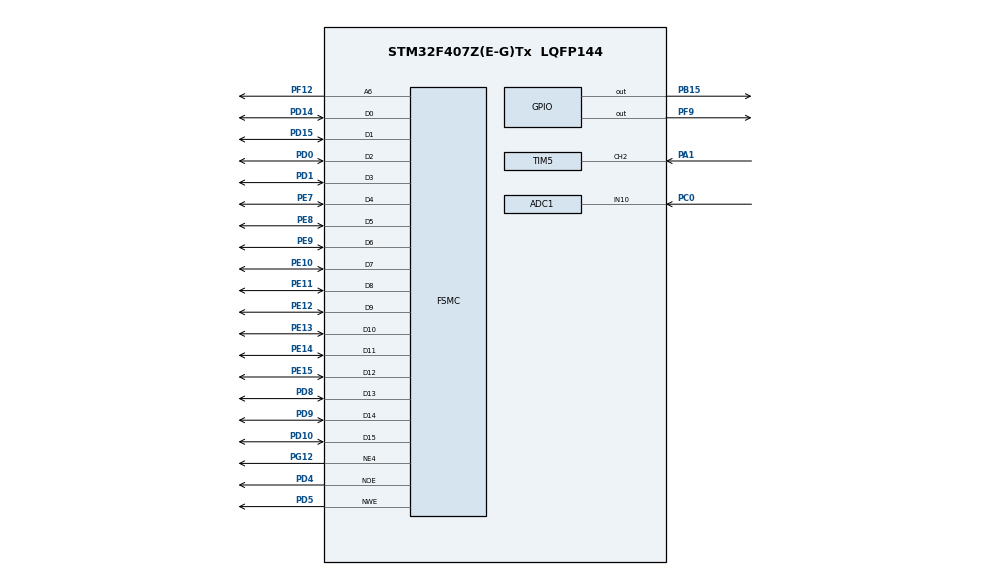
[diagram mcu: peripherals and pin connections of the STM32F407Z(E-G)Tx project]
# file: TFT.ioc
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ADC1.Channel-0\#ChannelRegularConversion=ADC_CHANNEL_10
ADC1.DMAContinuousRequests=ENABLE
ADC1.ExternalTrigConv=ADC_EXTERNALTRIGCONV_T2_TRGO
ADC1.InjNumberOfConversion=0
ADC1.NbrOfConversion=1
ADC1.NbrOfConversionFlag=1
ADC1.Rank-0\#ChannelRegularConversion=1
ADC1.SamplingTime-0\#ChannelRegularConversion=ADC_SAMPLETIME_3CYCLES
ADC1.master=1
Dma.ADC1.0.Direction=DMA_PERIPH_TO_MEMORY
Dma.ADC1.0.FIFOMode=DMA_FIFOMODE_DISABLE
Dma.ADC1.0.Instance=DMA2_Stream0
Dma.ADC1.0.MemDataAlignment=DMA_MDATAALIGN_HALFWORD
Dma.ADC1.0.MemInc=DMA_MINC_ENABLE
Dma.ADC1.0.Mode=DMA_CIRCULAR
Dma.ADC1.0.PeriphDataAlignment=DMA_PDATAALIGN_HALFWORD
Dma.ADC1.0.PeriphInc=DMA_PINC_DISABLE
Dma.ADC1.0.Priority=DMA_PRIORITY_VERY_HIGH
Dma.Request0=ADC1
FSMC.DataSetupTime4=60
FSMC.ExtendedAddressSetupTime4=9
FSMC.ExtendedDataSetupTime4=9
FSMC.ExtendedMode4=FSMC_EXTENDED_MODE_ENABLE
FSMC.WriteOperation4=FSMC_WRITE_OPERATION_ENABLE
Mcu.Family=STM32F4
Mcu.Name=STM32F407Z(E-G)Tx
Mcu.Package=LQFP144
NVIC.DMA2_Stream0_IRQn=true\:1\:0\:true\:false\:true\:false\:true\:true
NVIC.PriorityGroup=NVIC_PRIORITYGROUP_4
NVIC.TIM5_IRQn=true\:2\:0\:true\:false\:true\:true\:true\:true
PA1.Signal=S_TIM5_CH2
PA13.Mode=Serial_Wire
PA13.Signal=SYS_JTMS-SWDIO
PA14.Mode=Serial_Wire
PA14.Signal=SYS_JTCK-SWCLK
PB15.Signal=GPIO_Output
PC0.GPIO_Mode=GPIO_MODE_ANALOG
PC0.GPIO_PuPd=GPIO_NOPULL
PC0.Signal=ADCx_IN10
PD0.Signal=FSMC_D2_DA2
PD1.Signal=FSMC_D3_DA3
PD10.Signal=FSMC_D15_DA15
PD14.Signal=FSMC_D0_DA0
PD15.Signal=FSMC_D1_DA1
PD4.Signal=FSMC_NOE
PD5.Signal=FSMC_NWE
PD8.Signal=FSMC_D13_DA13
PD9.Signal=FSMC_D14_DA14
PE10.Signal=FSMC_D7_DA7
PE11.Signal=FSMC_D8_DA8
PE12.Signal=FSMC_D9_DA9
PE13.Signal=FSMC_D10_DA10
PE14.Signal=FSMC_D11_DA11
PE15.Signal=FSMC_D12_DA12
PE7.Signal=FSMC_D4_DA4
PE8.Signal=FSMC_D5_DA5
PE9.Signal=FSMC_D6_DA6
PF12.Signal=FSMC_A6
PF9.Signal=GPIO_Output
PG12.Mode=NorPsramChipSelect4_4
PG12.Signal=FSMC_NE4
PH0-OSC_IN.Mode=HSE-External-Oscillator
PH0-OSC_IN.Signal=RCC_OSC_IN
PH1-OSC_OUT.Mode=HSE-External-Oscillator
PH1-OSC_OUT.Signal=RCC_OSC_OUT
ProjectManager.HeapSize=0x200
ProjectManager.StackSize=0x400
ProjectManager.TargetToolchain=STM32CubeIDE
RCC.48MHZClocksFreq_Value=84000000
RCC.AHBFreq_Value=168000000
RCC.APB1CLKDivider=RCC_HCLK_DIV4
RCC.APB1Freq_Value=42000000
RCC.APB1TimFreq_Value=84000000
RCC.APB2CLKDivider=RCC_HCLK_DIV2
RCC.APB2Freq_Value=84000000
RCC.APB2TimFreq_Value=168000000
RCC.CortexFreq_Value=168000000
RCC.HCLKFreq_Value=168000000
RCC.HSE_VALUE=8000000
RCC.HSI_VALUE=16000000
RCC.LSE_VALUE=32768
RCC.PLLM=8
RCC.PLLN=168
RCC.SYSCLKFreq_VALUE=168000000
RCC.SYSCLKSource=RCC_SYSCLKSOURCE_PLLCLK
RCC.VCOOutputFreq_Value=336000000
SH.ADCx_IN10.0=ADC1_IN10,IN10
SH.FSMC_A6.0=FSMC_A6,A6_4
SH.FSMC_D0_DA0.0=FSMC_D0,16b-d4
SH.FSMC_D10_DA10.0=FSMC_D10,16b-d4
SH.FSMC_D11_DA11.0=FSMC_D11,16b-d4
SH.FSMC_D12_DA12.0=FSMC_D12,16b-d4
SH.FSMC_D13_DA13.0=FSMC_D13,16b-d4
SH.FSMC_D14_DA14.0=FSMC_D14,16b-d4
SH.FSMC_D15_DA15.0=FSMC_D15,16b-d4
SH.FSMC_D1_DA1.0=FSMC_D1,16b-d4
SH.FSMC_D2_DA2.0=FSMC_D2,16b-d4
SH.FSMC_D3_DA3.0=FSMC_D3,16b-d4
SH.FSMC_D4_DA4.0=FSMC_D4,16b-d4
SH.FSMC_D5_DA5.0=FSMC_D5,16b-d4
SH.FSMC_D6_DA6.0=FSMC_D6,16b-d4
SH.FSMC_D7_DA7.0=FSMC_D7,16b-d4
SH.FSMC_D8_DA8.0=FSMC_D8,16b-d4
SH.FSMC_D9_DA9.0=FSMC_D9,16b-d4
SH.FSMC_NOE.0=FSMC_NOE,Lcd4
SH.FSMC_NWE.0=FSMC_NWE,Lcd4
SH.S_TIM5_CH2.0=TIM5_CH2,TriggerSource_TI2FP2
SH.S_TIM5_CH2.1=TIM5_CH2,Input_Capture2_from_TI2
TIM2.AutoReloadPreload=TIM_AUTORELOAD_PRELOAD_ENABLE
TIM2.ClockDivision=TIM_CLOCKDIVISION_DIV1
TIM2.Period=83
TIM2.TIM_MasterOutputTrigger=TIM_TRGO_UPDATE
TIM2.TIM_MasterSlaveMode=TIM_MASTERSLAVEMODE_ENABLE
TIM5.Channel-Input_Capture2_from_TI2=TIM_CHANNEL_2
TIM5.Channel-Input_Capture1_from_TI2_63=TIM_CHANNEL_1
TIM5.ICPolarity_CH1=TIM_INPUTCHANNELPOLARITY_FALLING
VP_TIM2_VS_ClockSourceINT.Mode=Internal
VP_TIM5_VS_ClockSourceINT.Mode=Internal
VP_TIM5_VS_ControllerModeReset.Mode=Reset Mode
VP_TIM5_VS_indirect_ch2.Mode=Input_Capture1_from_TI2_63
board=custom

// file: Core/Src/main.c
#include "main.h"
#include "adc.h"
#include "dma.h"
#include "tim.h"
#include "gpio.h"
#include "fsmc.h"

/* USER CODE BEGIN Includes */
#include "lcd.h"
#include "app_ui.h"
#include "signal_analyzer.h"
/* USER CODE END Includes */

void SystemClock_Config(void);

int main(void)
{
    HAL_Init();
    SystemClock_Config();

    MX_GPIO_Init();
    MX_DMA_Init();
    MX_FSMC_Init();
    MX_ADC1_Init();
    MX_TIM2_Init();
    MX_TIM5_Init();

    /* USER CODE BEGIN 2 */
    HAL_GPIO_WritePin(GPIOB, GPIO_PIN_15, GPIO_PIN_RESET);
    HAL_Delay(300);
    lcd_init();

    if (!signal_analyzer_init())
    {
        Error_Handler();
    }

    app_ui_init();

    if (!signal_analyzer_start())
    {
        Error_Handler();
    }
    /* USER CODE END 2 */

    while (1)
    {
        /* USER CODE BEGIN 3 */
        signal_analyzer_process();
        app_ui_process(HAL_GetTick());
        /* USER CODE END 3 */
    }
}

void SystemClock_Config(void)
{
    RCC_OscInitTypeDef oscillator = {0};
    RCC_ClkInitTypeDef clocks = {0};

    __HAL_RCC_PWR_CLK_ENABLE();
    __HAL_PWR_VOLTAGESCALING_CONFIG(PWR_REGULATOR_VOLTAGE_SCALE1);

    oscillator.OscillatorType = RCC_OSCILLATORTYPE_HSI;
    oscillator.HSIState = RCC_HSI_ON;
    oscillator.HSICalibrationValue = RCC_HSICALIBRATION_DEFAULT;
    oscillator.PLL.PLLState = RCC_PLL_ON;
    oscillator.PLL.PLLSource = RCC_PLLSOURCE_HSI;
    oscillator.PLL.PLLM = 8;
    oscillator.PLL.PLLN = 168;
    oscillator.PLL.PLLP = RCC_PLLP_DIV2;
    oscillator.PLL.PLLQ = 4;

    if (HAL_RCC_OscConfig(&oscillator) != HAL_OK)
    {
        Error_Handler();
    }

    clocks.ClockType = RCC_CLOCKTYPE_HCLK |
                       RCC_CLOCKTYPE_SYSCLK |
                       RCC_CLOCKTYPE_PCLK1 |
                       RCC_CLOCKTYPE_PCLK2;
    clocks.SYSCLKSource = RCC_SYSCLKSOURCE_PLLCLK;
    clocks.AHBCLKDivider = RCC_SYSCLK_DIV2;
    clocks.APB1CLKDivider = RCC_HCLK_DIV2;
    clocks.APB2CLKDivider = RCC_HCLK_DIV1;

    if (HAL_RCC_ClockConfig(&clocks, FLASH_LATENCY_5) != HAL_OK)
    {
        Error_Handler();
    }
}

void Error_Handler(void)
{
    __disable_irq();
    while (1)
    {
    }
}
